VERSION 5.7 ;
  NOWIREEXTENSIONATPIN ON ;
  DIVIDERCHAR "/" ;
  BUSBITCHARS "[]" ;
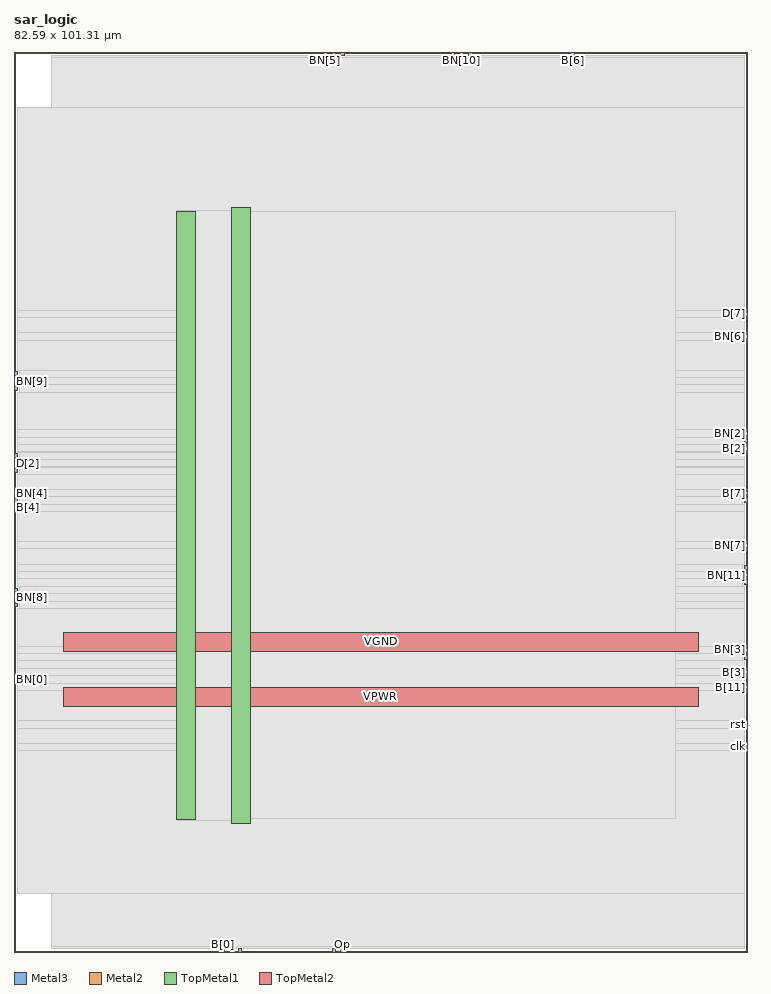
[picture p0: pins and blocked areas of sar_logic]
MACRO sar_logic
  CLASS BLOCK ;
  FOREIGN sar_logic ;
  ORIGIN 0.000 0.000 ;
  SIZE 82.590 BY 101.310 ;
  PIN BN[0]
    DIRECTION OUTPUT ;
    USE SIGNAL ;
    ANTENNADIFFAREA 0.708600 ;
    PORT
      LAYER Metal3 ;
        RECT 0.000 30.460 0.400 30.860 ;
    END
  END BN[0]
  PIN BN[10]
    DIRECTION OUTPUT ;
    USE SIGNAL ;
    ANTENNADIFFAREA 0.708600 ;
    PORT
      LAYER Metal2 ;
        RECT 50.200 100.910 50.600 101.310 ;
    END
  END BN[10]
  PIN BN[11]
    DIRECTION OUTPUT ;
    USE SIGNAL ;
    ANTENNADIFFAREA 0.708600 ;
    PORT
      LAYER Metal3 ;
        RECT 82.190 42.220 82.590 42.620 ;
    END
  END BN[11]
  PIN BN[1]
    DIRECTION OUTPUT ;
    USE SIGNAL ;
    ANTENNADIFFAREA 0.708600 ;
    PORT
      LAYER Metal3 ;
        RECT 0.000 55.660 0.400 56.060 ;
    END
  END BN[1]
  PIN BN[2]
    DIRECTION OUTPUT ;
    USE SIGNAL ;
    ANTENNADIFFAREA 0.708600 ;
    PORT
      LAYER Metal3 ;
        RECT 82.190 58.180 82.590 58.580 ;
    END
  END BN[2]
  PIN BN[3]
    DIRECTION OUTPUT ;
    USE SIGNAL ;
    ANTENNADIFFAREA 0.708600 ;
    PORT
      LAYER Metal3 ;
        RECT 82.190 33.820 82.590 34.220 ;
    END
  END BN[3]
  PIN BN[4]
    DIRECTION OUTPUT ;
    USE SIGNAL ;
    ANTENNADIFFAREA 0.708600 ;
    PORT
      LAYER Metal3 ;
        RECT 0.000 51.460 0.400 51.860 ;
    END
  END BN[4]
  PIN BN[5]
    DIRECTION OUTPUT ;
    USE SIGNAL ;
    ANTENNADIFFAREA 0.708600 ;
    PORT
      LAYER Metal2 ;
        RECT 34.840 100.910 35.240 101.310 ;
    END
  END BN[5]
  PIN BN[6]
    DIRECTION OUTPUT ;
    USE SIGNAL ;
    ANTENNADIFFAREA 0.708600 ;
    PORT
      LAYER Metal3 ;
        RECT 82.190 69.100 82.590 69.500 ;
    END
  END BN[6]
  PIN BN[7]
    DIRECTION OUTPUT ;
    USE SIGNAL ;
    ANTENNADIFFAREA 0.708600 ;
    PORT
      LAYER Metal3 ;
        RECT 82.190 45.580 82.590 45.980 ;
    END
  END BN[7]
  PIN BN[8]
    DIRECTION OUTPUT ;
    USE SIGNAL ;
    ANTENNADIFFAREA 0.708600 ;
    PORT
      LAYER Metal3 ;
        RECT 0.000 39.700 0.400 40.100 ;
    END
  END BN[8]
  PIN BN[9]
    DIRECTION OUTPUT ;
    USE SIGNAL ;
    ANTENNADIFFAREA 0.708600 ;
    PORT
      LAYER Metal3 ;
        RECT 0.000 64.060 0.400 64.460 ;
    END
  END BN[9]
  PIN B[0]
    DIRECTION OUTPUT ;
    USE SIGNAL ;
    ANTENNADIFFAREA 0.708600 ;
    PORT
      LAYER Metal2 ;
        RECT 23.320 0.000 23.720 0.400 ;
    END
  END B[0]
  PIN B[10]
    DIRECTION OUTPUT ;
    USE SIGNAL ;
    ANTENNADIFFAREA 0.708600 ;
    PORT
      LAYER Metal2 ;
        RECT 49.240 100.910 49.640 101.310 ;
    END
  END B[10]
  PIN B[11]
    DIRECTION OUTPUT ;
    USE SIGNAL ;
    ANTENNADIFFAREA 0.708600 ;
    PORT
      LAYER Metal3 ;
        RECT 82.190 29.620 82.590 30.020 ;
    END
  END B[11]
  PIN B[1]
    DIRECTION OUTPUT ;
    USE SIGNAL ;
    ANTENNADIFFAREA 0.708600 ;
    PORT
      LAYER Metal3 ;
        RECT 0.000 53.980 0.400 54.380 ;
    END
  END B[1]
  PIN B[2]
    DIRECTION OUTPUT ;
    USE SIGNAL ;
    ANTENNADIFFAREA 0.708600 ;
    PORT
      LAYER Metal3 ;
        RECT 82.190 56.500 82.590 56.900 ;
    END
  END B[2]
  PIN B[3]
    DIRECTION OUTPUT ;
    USE SIGNAL ;
    ANTENNADIFFAREA 0.708600 ;
    PORT
      LAYER Metal3 ;
        RECT 82.190 31.300 82.590 31.700 ;
    END
  END B[3]
  PIN B[4]
    DIRECTION OUTPUT ;
    USE SIGNAL ;
    ANTENNADIFFAREA 0.708600 ;
    PORT
      LAYER Metal3 ;
        RECT 0.000 49.780 0.400 50.180 ;
    END
  END B[4]
  PIN B[5]
    DIRECTION OUTPUT ;
    USE SIGNAL ;
    ANTENNADIFFAREA 0.708600 ;
    PORT
      LAYER Metal2 ;
        RECT 36.760 100.910 37.160 101.310 ;
    END
  END B[5]
  PIN B[6]
    DIRECTION OUTPUT ;
    USE SIGNAL ;
    ANTENNADIFFAREA 0.708600 ;
    PORT
      LAYER Metal2 ;
        RECT 62.680 100.910 63.080 101.310 ;
    END
  END B[6]
  PIN B[7]
    DIRECTION OUTPUT ;
    USE SIGNAL ;
    ANTENNADIFFAREA 0.708600 ;
    PORT
      LAYER Metal3 ;
        RECT 82.190 51.460 82.590 51.860 ;
    END
  END B[7]
  PIN B[8]
    DIRECTION OUTPUT ;
    USE SIGNAL ;
    ANTENNADIFFAREA 0.708600 ;
    PORT
      LAYER Metal3 ;
        RECT 0.000 38.860 0.400 39.260 ;
    END
  END B[8]
  PIN B[9]
    DIRECTION OUTPUT ;
    USE SIGNAL ;
    ANTENNADIFFAREA 0.708600 ;
    PORT
      LAYER Metal3 ;
        RECT 0.000 63.220 0.400 63.620 ;
    END
  END B[9]
  PIN D[0]
    DIRECTION OUTPUT ;
    USE SIGNAL ;
    ANTENNADIFFAREA 0.708600 ;
    PORT
      LAYER Metal3 ;
        RECT 82.190 41.380 82.590 41.780 ;
    END
  END D[0]
  PIN D[10]
    DIRECTION OUTPUT ;
    USE SIGNAL ;
    ANTENNADIFFAREA 0.708600 ;
    PORT
      LAYER Metal3 ;
        RECT 0.000 64.900 0.400 65.300 ;
    END
  END D[10]
  PIN D[11]
    DIRECTION OUTPUT ;
    USE SIGNAL ;
    ANTENNADIFFAREA 0.708600 ;
    PORT
      LAYER Metal2 ;
        RECT 51.160 100.910 51.560 101.310 ;
    END
  END D[11]
  PIN D[1]
    DIRECTION OUTPUT ;
    USE SIGNAL ;
    ANTENNADIFFAREA 0.708600 ;
    PORT
      LAYER Metal2 ;
        RECT 25.240 0.000 25.640 0.400 ;
    END
  END D[1]
  PIN D[2]
    DIRECTION OUTPUT ;
    USE SIGNAL ;
    ANTENNADIFFAREA 0.708600 ;
    PORT
      LAYER Metal3 ;
        RECT 0.000 54.820 0.400 55.220 ;
    END
  END D[2]
  PIN D[3]
    DIRECTION OUTPUT ;
    USE SIGNAL ;
    ANTENNADIFFAREA 0.708600 ;
    PORT
      LAYER Metal3 ;
        RECT 82.190 57.340 82.590 57.740 ;
    END
  END D[3]
  PIN D[4]
    DIRECTION OUTPUT ;
    USE SIGNAL ;
    ANTENNADIFFAREA 0.708600 ;
    PORT
      LAYER Metal3 ;
        RECT 82.190 32.980 82.590 33.380 ;
    END
  END D[4]
  PIN D[5]
    DIRECTION OUTPUT ;
    USE SIGNAL ;
    ANTENNADIFFAREA 0.708600 ;
    PORT
      LAYER Metal3 ;
        RECT 0.000 50.620 0.400 51.020 ;
    END
  END D[5]
  PIN D[6]
    DIRECTION OUTPUT ;
    USE SIGNAL ;
    ANTENNADIFFAREA 0.708600 ;
    PORT
      LAYER Metal2 ;
        RECT 35.800 100.910 36.200 101.310 ;
    END
  END D[6]
  PIN D[7]
    DIRECTION OUTPUT ;
    USE SIGNAL ;
    ANTENNADIFFAREA 0.708600 ;
    PORT
      LAYER Metal3 ;
        RECT 82.190 71.620 82.590 72.020 ;
    END
  END D[7]
  PIN D[8]
    DIRECTION OUTPUT ;
    USE SIGNAL ;
    ANTENNADIFFAREA 0.708600 ;
    PORT
      LAYER Metal3 ;
        RECT 82.190 50.620 82.590 51.020 ;
    END
  END D[8]
  PIN D[9]
    DIRECTION OUTPUT ;
    USE SIGNAL ;
    ANTENNADIFFAREA 0.708600 ;
    PORT
      LAYER Metal3 ;
        RECT 0.000 40.540 0.400 40.940 ;
    END
  END D[9]
  PIN Om
    DIRECTION INPUT ;
    USE SIGNAL ;
    ANTENNAGATEAREA 0.180700 ;
    PORT
      LAYER Metal2 ;
        RECT 35.800 0.000 36.200 0.400 ;
    END
  END Om
  PIN Op
    DIRECTION INPUT ;
    USE SIGNAL ;
    ANTENNAGATEAREA 0.180700 ;
    PORT
      LAYER Metal2 ;
        RECT 36.760 0.000 37.160 0.400 ;
    END
  END Op
  PIN VGND
    DIRECTION INOUT ;
    USE GROUND ;
    PORT
      LAYER TopMetal1 ;
        RECT 24.460 14.490 26.660 83.790 ;
    END
    PORT
      LAYER TopMetal2 ;
        RECT 5.540 33.820 77.020 36.020 ;
    END
  END VGND
  PIN VPWR
    DIRECTION INOUT ;
    USE POWER ;
    PORT
      LAYER TopMetal1 ;
        RECT 18.260 14.900 20.460 83.380 ;
    END
    PORT
      LAYER TopMetal2 ;
        RECT 5.540 27.620 77.020 29.820 ;
    END
  END VPWR
  PIN clk
    DIRECTION INPUT ;
    USE SIGNAL ;
    ANTENNAGATEAREA 0.725400 ;
    PORT
      LAYER Metal3 ;
        RECT 82.190 22.900 82.590 23.300 ;
    END
  END clk
  PIN rst
    DIRECTION INPUT ;
    USE SIGNAL ;
    ANTENNAGATEAREA 0.213200 ;
    PORT
      LAYER Metal3 ;
        RECT 82.190 25.420 82.590 25.820 ;
    END
  END rst
  PIN sign
    DIRECTION OUTPUT ;
    USE SIGNAL ;
    ANTENNADIFFAREA 0.708600 ;
    PORT
      LAYER Metal3 ;
        RECT 82.190 43.060 82.590 43.460 ;
    END
  END sign
  OBS
      LAYER GatPoly ;
        RECT 5.760 14.970 76.800 83.310 ;
      LAYER Metal1 ;
        RECT 5.760 14.900 76.800 83.380 ;
      LAYER Metal2 ;
        RECT 4.215 100.700 34.630 100.910 ;
        RECT 35.450 100.700 35.590 100.910 ;
        RECT 36.410 100.700 36.550 100.910 ;
        RECT 37.370 100.700 49.030 100.910 ;
        RECT 49.850 100.700 49.990 100.910 ;
        RECT 50.810 100.700 50.950 100.910 ;
        RECT 51.770 100.700 62.470 100.910 ;
        RECT 63.290 100.700 82.185 100.910 ;
        RECT 4.215 0.610 82.185 100.700 ;
        RECT 4.215 0.400 23.110 0.610 ;
        RECT 23.930 0.400 25.030 0.610 ;
        RECT 25.850 0.400 35.590 0.610 ;
        RECT 36.410 0.400 36.550 0.610 ;
        RECT 37.370 0.400 82.185 0.610 ;
      LAYER Metal3 ;
        RECT 0.400 72.230 82.225 95.020 ;
        RECT 0.400 71.410 81.980 72.230 ;
        RECT 0.400 69.710 82.225 71.410 ;
        RECT 0.400 68.890 81.980 69.710 ;
        RECT 0.400 65.510 82.225 68.890 ;
        RECT 0.610 64.690 82.225 65.510 ;
        RECT 0.400 64.670 82.225 64.690 ;
        RECT 0.610 63.850 82.225 64.670 ;
        RECT 0.400 63.830 82.225 63.850 ;
        RECT 0.610 63.010 82.225 63.830 ;
        RECT 0.400 58.790 82.225 63.010 ;
        RECT 0.400 57.970 81.980 58.790 ;
        RECT 0.400 57.950 82.225 57.970 ;
        RECT 0.400 57.130 81.980 57.950 ;
        RECT 0.400 57.110 82.225 57.130 ;
        RECT 0.400 56.290 81.980 57.110 ;
        RECT 0.400 56.270 82.225 56.290 ;
        RECT 0.610 55.450 82.225 56.270 ;
        RECT 0.400 55.430 82.225 55.450 ;
        RECT 0.610 54.610 82.225 55.430 ;
        RECT 0.400 54.590 82.225 54.610 ;
        RECT 0.610 53.770 82.225 54.590 ;
        RECT 0.400 52.070 82.225 53.770 ;
        RECT 0.610 51.250 81.980 52.070 ;
        RECT 0.400 51.230 82.225 51.250 ;
        RECT 0.610 50.410 81.980 51.230 ;
        RECT 0.400 50.390 82.225 50.410 ;
        RECT 0.610 49.570 82.225 50.390 ;
        RECT 0.400 46.190 82.225 49.570 ;
        RECT 0.400 45.370 81.980 46.190 ;
        RECT 0.400 43.670 82.225 45.370 ;
        RECT 0.400 42.850 81.980 43.670 ;
        RECT 0.400 42.830 82.225 42.850 ;
        RECT 0.400 42.010 81.980 42.830 ;
        RECT 0.400 41.990 82.225 42.010 ;
        RECT 0.400 41.170 81.980 41.990 ;
        RECT 0.400 41.150 82.225 41.170 ;
        RECT 0.610 40.330 82.225 41.150 ;
        RECT 0.400 40.310 82.225 40.330 ;
        RECT 0.610 39.490 82.225 40.310 ;
        RECT 0.400 39.470 82.225 39.490 ;
        RECT 0.610 38.650 82.225 39.470 ;
        RECT 0.400 34.430 82.225 38.650 ;
        RECT 0.400 33.610 81.980 34.430 ;
        RECT 0.400 33.590 82.225 33.610 ;
        RECT 0.400 32.770 81.980 33.590 ;
        RECT 0.400 31.910 82.225 32.770 ;
        RECT 0.400 31.090 81.980 31.910 ;
        RECT 0.400 31.070 82.225 31.090 ;
        RECT 0.610 30.250 82.225 31.070 ;
        RECT 0.400 30.230 82.225 30.250 ;
        RECT 0.400 29.410 81.980 30.230 ;
        RECT 0.400 26.030 82.225 29.410 ;
        RECT 0.400 25.210 81.980 26.030 ;
        RECT 0.400 23.510 82.225 25.210 ;
        RECT 0.400 22.690 81.980 23.510 ;
        RECT 0.400 6.620 82.225 22.690 ;
      LAYER Metal4 ;
        RECT 18.440 14.975 74.500 83.305 ;
      LAYER Metal5 ;
        RECT 18.395 14.810 26.525 83.470 ;
  END
END sar_logic
END LIBRARY

